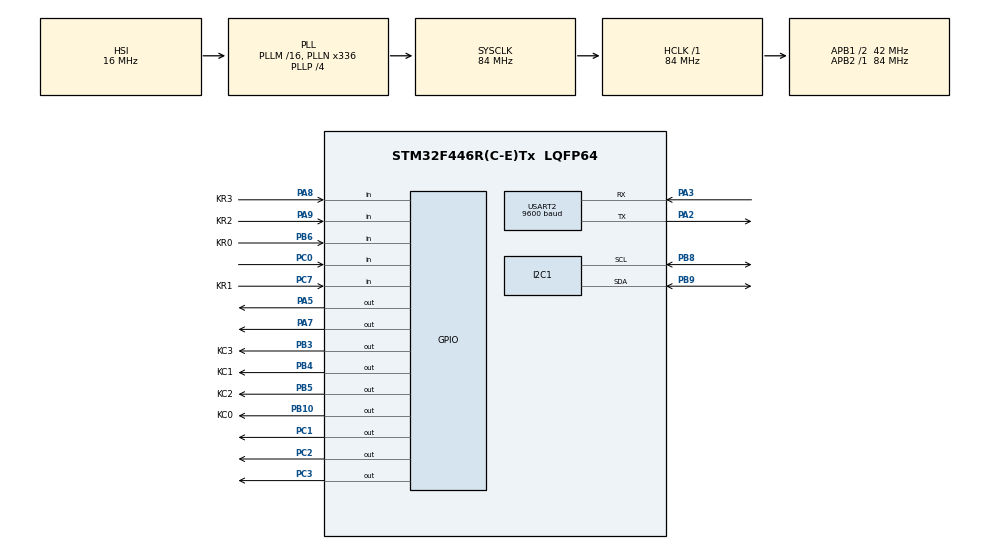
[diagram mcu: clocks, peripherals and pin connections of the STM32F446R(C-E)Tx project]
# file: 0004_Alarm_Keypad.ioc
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FREERTOS.Tasks01=defaultTask,0,128,StartDefaultTask,Default,NULL,Dynamic,NULL,NULL;taskPIR,-3,128,StartTaskPIR,Default,NULL,Dynamic,NULL,NULL;taskBuzzer,-3,128,StartTaskBuzzer,Default,NULL,Dynamic,NULL,NULL
I2C1.I2C_Mode=I2C_Fast
Mcu.Family=STM32F4
Mcu.Name=STM32F446R(C-E)Tx
Mcu.Package=LQFP64
NVIC.PriorityGroup=NVIC_PRIORITYGROUP_4
NVIC.TIM6_DAC_IRQn=true\:15\:0\:false\:false\:true\:false\:false\:true\:true
NVIC.TimeBase=TIM6_DAC_IRQn
NVIC.TimeBaseIP=TIM6
PA13.Mode=Serial_Wire
PA13.Signal=SYS_JTMS-SWDIO
PA14.Mode=Serial_Wire
PA14.Signal=SYS_JTCK-SWCLK
PA2.Mode=Asynchronous
PA2.Signal=USART2_TX
PA3.Mode=Asynchronous
PA3.Signal=USART2_RX
PA5.Signal=GPIO_Output
PA7.Signal=GPIO_Output
PA8.GPIO_Label=KR3
PA8.GPIO_PuPd=GPIO_PULLDOWN
PA8.Signal=GPIO_Input
PA9.GPIO_Label=KR2
PA9.GPIO_PuPd=GPIO_PULLDOWN
PA9.Signal=GPIO_Input
PB10.GPIO_Label=KC0
PB10.Signal=GPIO_Output
PB3.GPIO_Label=KC3
PB3.Signal=GPIO_Output
PB4.GPIO_Label=KC1
PB4.Signal=GPIO_Output
PB5.GPIO_Label=KC2
PB5.Signal=GPIO_Output
PB6.GPIO_Label=KR0
PB6.GPIO_PuPd=GPIO_PULLDOWN
PB6.Signal=GPIO_Input
PB8.Mode=I2C
PB8.Signal=I2C1_SCL
PB9.Mode=I2C
PB9.Signal=I2C1_SDA
PC0.Signal=GPIO_Input
PC1.Signal=GPIO_Output
PC14-OSC32_IN.Mode=LSE-External-Oscillator
PC14-OSC32_IN.Signal=RCC_OSC32_IN
PC15-OSC32_OUT.Mode=LSE-External-Oscillator
PC15-OSC32_OUT.Signal=RCC_OSC32_OUT
PC2.Signal=GPIO_Output
PC3.Signal=GPIO_Output
PC7.GPIO_Label=KR1
PC7.GPIO_PuPd=GPIO_PULLDOWN
PC7.Signal=GPIO_Input
PH0-OSC_IN.Mode=HSE-External-Oscillator
PH0-OSC_IN.Signal=RCC_OSC_IN
PH1-OSC_OUT.Mode=HSE-External-Oscillator
PH1-OSC_OUT.Signal=RCC_OSC_OUT
ProjectManager.HeapSize=0x200
ProjectManager.StackSize=0x400
ProjectManager.TargetToolchain=STM32CubeIDE
RCC.48MHZClocksFreq_Value=84000000
RCC.AHBFreq_Value=84000000
RCC.APB1CLKDivider=RCC_HCLK_DIV2
RCC.APB1Freq_Value=42000000
RCC.APB1TimFreq_Value=84000000
RCC.APB2Freq_Value=84000000
RCC.APB2TimFreq_Value=84000000
RCC.CortexFreq_Value=84000000
RCC.FLatency-AdvancedSettings=FLASH_LATENCY_2
RCC.HCLKFreq_Value=84000000
RCC.HSE_VALUE=8000000
RCC.HSI_VALUE=16000000
RCC.PLLN=336
RCC.PLLP=RCC_PLLP_DIV4
RCC.SYSCLKFreq_VALUE=84000000
RCC.SYSCLKSource=RCC_SYSCLKSOURCE_PLLCLK
RCC.USBFreq_Value=168000000
RCC.VCOOutputFreq_Value=336000000
USART2.BaudRate=9600
USART2.VirtualMode=VM_ASYNC
VP_FREERTOS_VS_CMSIS_V1.Mode=CMSIS_V1
VP_SYS_VS_tim6.Mode=TIM6
board=NUCLEO-F446RE

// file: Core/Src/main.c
/* USER CODE BEGIN Header */
/**
 ******************************************************************************
 * @file           : main.c
 * @brief          : Main program body
 ******************************************************************************
 * @attention
 *
 * Copyright (c) 2024 STMicroelectronics.
 * All rights reserved.
 *
 * This software is licensed under terms that can be found in the LICENSE file
 * in the root directory of this software component.
 * If no LICENSE file comes with this software, it is provided AS-IS.
 *
 ******************************************************************************
 */
/* USER CODE END Header */
#include "main.h"
#include "cmsis_os.h"

/* USER CODE BEGIN Includes */
#include "Keypad4X4.h"
#include <stdio.h>
#include <string.h>
#include <stdlib.h>
#include "fonts.h"
#include "ssd1306.h"

/* USER CODE END Includes */

I2C_HandleTypeDef hi2c1;

UART_HandleTypeDef huart2;

osThreadId defaultTaskHandle;
osThreadId task01Handle;
osThreadId task02Handle;
osThreadId task03Handle;
osMessageQId queue01Handle;
/* USER CODE BEGIN PV */
extern char key;
char hold[4];
/* USER CODE END PV */

void SystemClock_Config(void);
static void MX_GPIO_Init(void);
static void MX_USART2_UART_Init(void);
static void MX_I2C1_Init(void);
void BuzzerTask(void const *argument);
void LCDTask(void const *argument);
void KeypadTask(void const *argument);
void PIRTask(void const *argument);

int buzzer = 0; //Bool to check if buzzer is on or off
int movement = 0; //Bool to check if mouvement is detected or not
int armed = 0; //Bool to check if system is armed or not

int main(void) {

	/* MCU Configuration--------------------------------------------------------*/

	/* Reset of all peripherals, Initializes the Flash interface and the Systick. */
	HAL_Init();

	/* Configure the system clock */
	SystemClock_Config();

	/* Initialize all configured peripherals */
	MX_GPIO_Init();
	MX_USART2_UART_Init();
	MX_I2C1_Init();
	/* USER CODE BEGIN 2 */
	SSD1306_Init();
	SSD1306_GotoXY(0, 0);
	SSD1306_Puts("Set Code", &Font_11x18, 1);
	HAL_UART_Transmit(&huart2, (uint8_t *)"Set Code\r\n", 11, 100);
	SSD1306_GotoXY(0, 30);
	HAL_UART_Transmit(&huart2, (uint8_t *)"Code:", 5, 100);
	SSD1306_Puts("Code:", &Font_11x18, 1);
	SSD1306_UpdateScreen();

	/* USER CODE END 2 */

	/* Create the queue(s) */
	/* definition and creation of queue01 */
	osMessageQDef(queue01, 16, char);
	queue01Handle = osMessageCreate(osMessageQ(queue01), NULL);

	/* Create the thread(s) */
	/* definition and creation of defaultTask */
	osThreadDef(defaultTask, BuzzerTask, osPriorityAboveNormal, 0, 128);
	defaultTaskHandle = osThreadCreate(osThread(defaultTask), NULL);

	/* definition and creation of task01 */
	osThreadDef(task01, LCDTask, osPriorityAboveNormal, 0, 128);
	task01Handle = osThreadCreate(osThread(task01), NULL);

	/* definition and creation of task02 */
	osThreadDef(task02, KeypadTask, osPriorityNormal, 0, 128);
	task02Handle = osThreadCreate(osThread(task02), NULL);

	/* USER CODE BEGIN RTOS_THREADS */
	osThreadDef(task03, PIRTask, osPriorityAboveNormal, 0, 128);
	task03Handle = osThreadCreate(osThread(task03), NULL);
	/* add threads, ... */
	/* USER CODE END RTOS_THREADS */
	/* Start scheduler */
	osKernelStart();
	/* We should never get here as control is now taken by the scheduler */
	/* Infinite loop */
	/* USER CODE BEGIN WHILE */
	while (1) {
	}
	/* USER CODE END 3 */
}

void SystemClock_Config(void) {
	RCC_OscInitTypeDef RCC_OscInitStruct = { 0 };
	RCC_ClkInitTypeDef RCC_ClkInitStruct = { 0 };

	/** Configure the main internal regulator output voltage
	 */
	__HAL_RCC_PWR_CLK_ENABLE();
	__HAL_PWR_VOLTAGESCALING_CONFIG(PWR_REGULATOR_VOLTAGE_SCALE3);

	/** Initializes the RCC Oscillators according to the specified parameters
	 * in the RCC_OscInitTypeDef structure.
	 */
	RCC_OscInitStruct.OscillatorType = RCC_OSCILLATORTYPE_HSI;
	RCC_OscInitStruct.HSIState = RCC_HSI_ON;
	RCC_OscInitStruct.HSICalibrationValue = RCC_HSICALIBRATION_DEFAULT;
	RCC_OscInitStruct.PLL.PLLState = RCC_PLL_ON;
	RCC_OscInitStruct.PLL.PLLSource = RCC_PLLSOURCE_HSI;
	RCC_OscInitStruct.PLL.PLLM = 16;
	RCC_OscInitStruct.PLL.PLLN = 336;
	RCC_OscInitStruct.PLL.PLLP = RCC_PLLP_DIV4;
	RCC_OscInitStruct.PLL.PLLQ = 2;
	RCC_OscInitStruct.PLL.PLLR = 2;
	if (HAL_RCC_OscConfig(&RCC_OscInitStruct) != HAL_OK) {
		Error_Handler();
	}

	/** Initializes the CPU, AHB and APB buses clocks
	 */
	RCC_ClkInitStruct.ClockType = RCC_CLOCKTYPE_HCLK | RCC_CLOCKTYPE_SYSCLK
			| RCC_CLOCKTYPE_PCLK1 | RCC_CLOCKTYPE_PCLK2;
	RCC_ClkInitStruct.SYSCLKSource = RCC_SYSCLKSOURCE_PLLCLK;
	RCC_ClkInitStruct.AHBCLKDivider = RCC_SYSCLK_DIV1;
	RCC_ClkInitStruct.APB1CLKDivider = RCC_HCLK_DIV2;
	RCC_ClkInitStruct.APB2CLKDivider = RCC_HCLK_DIV1;

	if (HAL_RCC_ClockConfig(&RCC_ClkInitStruct, FLASH_LATENCY_2) != HAL_OK) {
		Error_Handler();
	}
}

static void MX_I2C1_Init(void) {

	hi2c1.Instance = I2C1;
	hi2c1.Init.ClockSpeed = 400000;
	hi2c1.Init.DutyCycle = I2C_DUTYCYCLE_2;
	hi2c1.Init.OwnAddress1 = 0;
	hi2c1.Init.AddressingMode = I2C_ADDRESSINGMODE_7BIT;
	hi2c1.Init.DualAddressMode = I2C_DUALADDRESS_DISABLE;
	hi2c1.Init.OwnAddress2 = 0;
	hi2c1.Init.GeneralCallMode = I2C_GENERALCALL_DISABLE;
	hi2c1.Init.NoStretchMode = I2C_NOSTRETCH_DISABLE;
	if (HAL_I2C_Init(&hi2c1) != HAL_OK) {
		Error_Handler();
	}

}

static void MX_USART2_UART_Init(void) {

	huart2.Instance = USART2;
	huart2.Init.BaudRate = 9600;
	huart2.Init.WordLength = UART_WORDLENGTH_8B;
	huart2.Init.StopBits = UART_STOPBITS_1;
	huart2.Init.Parity = UART_PARITY_NONE;
	huart2.Init.Mode = UART_MODE_TX_RX;
	huart2.Init.HwFlowCtl = UART_HWCONTROL_NONE;
	huart2.Init.OverSampling = UART_OVERSAMPLING_16;
	if (HAL_UART_Init(&huart2) != HAL_OK) {
		Error_Handler();
	}

}

static void MX_GPIO_Init(void) {
	GPIO_InitTypeDef GPIO_InitStruct = { 0 };

	/* GPIO Ports Clock Enable */
	__HAL_RCC_GPIOC_CLK_ENABLE();
	__HAL_RCC_GPIOH_CLK_ENABLE();
	__HAL_RCC_GPIOA_CLK_ENABLE();
	__HAL_RCC_GPIOB_CLK_ENABLE();

	/*Configure GPIO pin Output Level */

	HAL_GPIO_WritePin(GPIOA, GPIO_PIN_5 | GPIO_PIN_6 | GPIO_PIN_7 | GPIO_PIN_15, GPIO_PIN_RESET);

	/*Configure GPIO pin Output Level */
	HAL_GPIO_WritePin(GPIOB, KC0_Pin | KC3_Pin | KC1_Pin | KC2_Pin,
			GPIO_PIN_RESET);

	/*Configure GPIO pin : PA5 */
	GPIO_InitStruct.Pin = GPIO_PIN_15;
	GPIO_InitStruct.Mode = GPIO_MODE_INPUT;
	GPIO_InitStruct.Pull = GPIO_NOPULL;
		HAL_GPIO_Init(GPIOA, &GPIO_InitStruct);

	/*Configure GPIO pin : PA5 */
	GPIO_InitStruct.Pin = GPIO_PIN_5;
	GPIO_InitStruct.Mode = GPIO_MODE_OUTPUT_PP;
	GPIO_InitStruct.Pull = GPIO_NOPULL;
	GPIO_InitStruct.Speed = GPIO_SPEED_FREQ_LOW;
	HAL_GPIO_Init(GPIOA, &GPIO_InitStruct);

	GPIO_InitStruct.Pin = GPIO_PIN_6;
	GPIO_InitStruct.Mode = GPIO_MODE_OUTPUT_PP;
	GPIO_InitStruct.Pull = GPIO_NOPULL;
	GPIO_InitStruct.Speed = GPIO_SPEED_FREQ_LOW;
	HAL_GPIO_Init(GPIOA, &GPIO_InitStruct);

	GPIO_InitStruct.Pin = GPIO_PIN_7;
	GPIO_InitStruct.Mode = GPIO_MODE_OUTPUT_PP;
	GPIO_InitStruct.Pull = GPIO_NOPULL;
	GPIO_InitStruct.Speed = GPIO_SPEED_FREQ_LOW;
	HAL_GPIO_Init(GPIOA, &GPIO_InitStruct);

	/*Configure GPIO pins : KC0_Pin KC3_Pin KC1_Pin KC2_Pin */
	GPIO_InitStruct.Pin = KC0_Pin | KC3_Pin | KC1_Pin | KC2_Pin;
	GPIO_InitStruct.Mode = GPIO_MODE_OUTPUT_PP;
	GPIO_InitStruct.Pull = GPIO_NOPULL;
	GPIO_InitStruct.Speed = GPIO_SPEED_FREQ_LOW;
	HAL_GPIO_Init(GPIOB, &GPIO_InitStruct);

	/*Configure GPIO pin : KR1_Pin */
	GPIO_InitStruct.Pin = KR1_Pin;
	GPIO_InitStruct.Mode = GPIO_MODE_INPUT;
	GPIO_InitStruct.Pull = GPIO_PULLDOWN;
	HAL_GPIO_Init(KR1_GPIO_Port, &GPIO_InitStruct);

	/*Configure GPIO pins : KR3_Pin KR2_Pin */
	GPIO_InitStruct.Pin = KR3_Pin | KR2_Pin;
	GPIO_InitStruct.Mode = GPIO_MODE_INPUT;
	GPIO_InitStruct.Pull = GPIO_PULLDOWN;
	HAL_GPIO_Init(GPIOA, &GPIO_InitStruct);

	/*Configure GPIO pin : KR0_Pin */
	GPIO_InitStruct.Pin = KR0_Pin;
	GPIO_InitStruct.Mode = GPIO_MODE_INPUT;
	GPIO_InitStruct.Pull = GPIO_PULLDOWN;
	HAL_GPIO_Init(KR0_GPIO_Port, &GPIO_InitStruct);

}

void BuzzerTask(void const *argument) {
	/* USER CODE BEGIN 5 */
	/* Infinite loop */
	for (;;) {
		if (armed && buzzer) {
			HAL_GPIO_WritePin(GPIOA, GPIO_PIN_6, SET); // activate the buzzer
			osDelay(100);

			HAL_GPIO_WritePin(GPIOA, GPIO_PIN_6, RESET); // stop the buzzer
			osDelay(100);
		} else {
			// If the system is not armed or does not have a buzzer, make sure the buzzer is off
			HAL_GPIO_WritePin(GPIOA, GPIO_PIN_6, RESET);
			osDelay(100);
		}

		osDelay(100);
	}
	/* USER CODE END 5 */
}

void LCDTask(void const *argument) {
	/* USER CODE BEGIN LCDTask */
	/* Infinite loop */

	char receivedKey;
	uint8_t codeLength = 0; // Track the number of entered characters
	char userCode[7] = { 0 }; // Array to store the entered code
	uint8_t maxCodeLength = 6; // Adjust based on requirements
	uint8_t minCodeLength = 4;
	char correctCode[7] = { 0 }; // Example of a correct code for comparison

	//Use to check if first time that the system is Used
	//If 1, means true so the user must enter the new password for system
	int initial = 1;

	for (;;) {

		if (armed) {
			HAL_GPIO_WritePin(GPIOA, GPIO_PIN_6, SET);
			HAL_GPIO_WritePin(GPIOA, GPIO_PIN_7, RESET);
			//osDelay(2000);
		} else {
			HAL_GPIO_WritePin(GPIOA, GPIO_PIN_7, SET);
			HAL_GPIO_WritePin(GPIOA, GPIO_PIN_6, RESET);
		}

		if(initial){
			HAL_GPIO_WritePin(GPIOA, GPIO_PIN_15, RESET);
			HAL_GPIO_WritePin(GPIOA, GPIO_PIN_6, SET);
			HAL_GPIO_WritePin(GPIOA, GPIO_PIN_7, SET);
		}

		//	Use queue to keep track of key pressed
		if (xQueueReceive(queue01Handle, &receivedKey, portMAX_DELAY) == pdPASS) {

			//Used at the start of the application so the user can enter the code that will be use to armed and unarmed the system
			if (receivedKey == '#' && codeLength >= minCodeLength && initial) { // Enter/confirm key or max length reached
				// Check if the entered code is correct
				strncpy(correctCode, userCode, sizeof(correctCode));

				//Set the userCode as the new password
				SSD1306_Clear();
				SSD1306_GotoXY(0, 0);
				HAL_UART_Transmit(&huart2, (uint8_t *)"Code Set\r\n", 10, 100);
				SSD1306_Puts("Code Set", &Font_11x18, 1);
				SSD1306_UpdateScreen();

				HAL_Delay(2000);

				armed = 1;

				//Set as armed
				SSD1306_Clear();
				SSD1306_GotoXY(0, 0);
				SSD1306_Puts("Armed", &Font_11x18, 1);
				HAL_UART_Transmit(&huart2, (uint8_t *)"Armed\r\n", 8, 100);
				SSD1306_GotoXY(0, 30); // Adjust Y position based on your font size
				HAL_UART_Transmit(&huart2, (uint8_t *)"Code:", 5, 100);
				SSD1306_Puts("Code:", &Font_11x18, 1);

				memset(userCode, 0, sizeof(userCode));
				codeLength = 0;

				initial = 0;
			}

			// Enter/confirm key or max length reached
				else if (receivedKey == '#' && codeLength >= minCodeLength && !initial) {
				// Check if the entered code is correct
				if (strncmp(userCode, correctCode, maxCodeLength) == 0) {
					// Code is correct
					SSD1306_Clear();
					SSD1306_GotoXY(0, 0);
					SSD1306_Puts("Success", &Font_11x18, 1);

					HAL_UART_Transmit(&huart2, (uint8_t *)"Success\r\n", 10, 100);

					if (armed) {
						armed = 0;
					} else {
						armed = 1;
					}
				} else {
					// Code is incorrect
					SSD1306_Clear();
					SSD1306_GotoXY(0, 0);
					SSD1306_Puts("Failed", &Font_11x18, 1);
					HAL_UART_Transmit(&huart2, (uint8_t *)"Failed\r\n", 9, 100);
					//Activate buzzer
					buzzer= 1;

				}

				SSD1306_UpdateScreen();
				HAL_Delay(2000); // Display message for 2 seconds

				// Reset display and code length for next entry
				SSD1306_Clear();
				SSD1306_GotoXY(0, 0);

				//Check if armed
				if (armed) {
					SSD1306_Puts("Armed", &Font_11x18, 1);
					HAL_UART_Transmit(&huart2, (uint8_t *)"Armed\r\n", 8, 100);

				} else {
					SSD1306_Puts("Not Armed", &Font_11x18, 1);
					HAL_UART_Transmit(&huart2, (uint8_t *)"Not Armed\r\n", 12, 100);

				}
				SSD1306_GotoXY(0, 30); // Adjust Y position based on your font size
				HAL_UART_Transmit(&huart2, (uint8_t *)"Code:", 5, 100);
				SSD1306_Puts("Code:", &Font_11x18, 1);
				SSD1306_UpdateScreen();
				memset(userCode, 0, sizeof(userCode)); // Clear the entered code
				codeLength = 0;

			} else {

				// Add received key to the entered code and update the display with an additional asterisk
				if (codeLength < maxCodeLength) { // Prevent buffer overflow
					userCode[codeLength] = receivedKey; // Store the received key
					SSD1306_Puts("*", &Font_11x18, 1);
					HAL_UART_Transmit(&huart2, (uint8_t *)"*", 1, 100);
					SSD1306_UpdateScreen();
					//Update code Length
					codeLength++;
				} else {
					printf("Error: Max Code Length Reached!\r\n");
				}
			}
		}
	}

	/* USER CODE END LCDTask */
}

void KeypadTask(void const *argument) {
	const TickType_t xDelay = 20 / portTICK_PERIOD_MS; // Debounce delay
	char keyEntered; // To hold the key to be sent

	for (;;) {
		keyEntered = Get_Key(); // Assume Get_Key() is debounced and returns '\0' if no key is pressed
		if (keyEntered != '\0') { // Check if a key is pressed
			// Send the key press to the display task
			if (xQueueSend(queue01Handle, &keyEntered, portMAX_DELAY) != pdPASS) {
				printf("Error: Data couldn't be sent from KeypadTask\r\n");
			}
		}
		vTaskDelay(xDelay); // Wait for the next cycle
	}
	/* USER CODE END LCDTask */
}

void PIRTask(void const *argument) {
	/* USER CODE BEGIN PIRTask */
	/* Infinite loop */
	GPIO_PinState pirState;
	/* Infinite loop */
	for (;;) {

		pirState = HAL_GPIO_ReadPin(GPIOA, GPIO_PIN_15);

		if (pirState == GPIO_PIN_SET && armed) {
			HAL_UART_Transmit(&huart2, (uint8_t *)"Movement\r\n", 13, 100);
			buzzer = 1;
		} else {
			if(armed){
				//pirState = GPIO_PIN_RESET;
				HAL_UART_Transmit(&huart2, (uint8_t *)"No Movement\r\n", 13, 100);
			}
			buzzer = 0; // No buzzer
		}
		osDelay(100); // Check every 100ms
	}
	/* USER CODE END PIRTask */
}

void HAL_TIM_PeriodElapsedCallback(TIM_HandleTypeDef *htim) {
	if (htim->Instance == TIM6) {
		HAL_IncTick();
	}
}

void Error_Handler(void) {
	__disable_irq();
	while (1) {
	}
}
